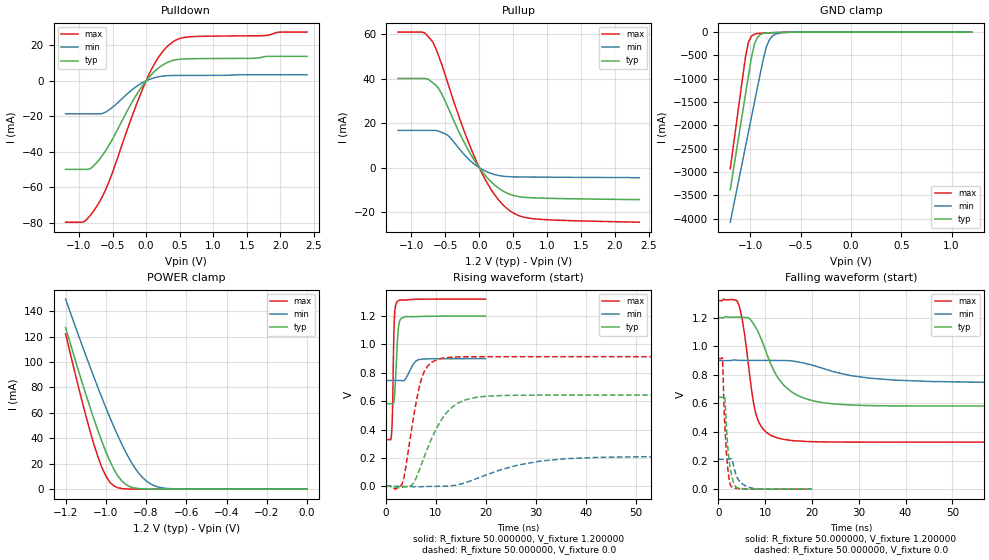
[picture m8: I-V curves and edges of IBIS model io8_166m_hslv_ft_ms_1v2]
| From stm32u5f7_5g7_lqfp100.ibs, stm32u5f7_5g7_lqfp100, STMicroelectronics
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|   Model io8_166m_hslv_ft_ms_1v2
[Model]  io8_166m_hslv_ft_ms_1v2
Model_type I/O
Polarity   Non-Inverting
Enable   Active-Low
Vinl =   0.360000V
Vinh =   0.840000V
Vmeas =  0.600000V
Cref =   50.000000pF
Rref =   100.000000M
Vref =   0.0V
C_comp   3.151700pF   3.087200pF   3.197900pF
[Temperature Range]   25.000000   0.140000k   -40.000000
[Pullup Reference]   1.200000V   0.900000V   1.320000V
[Pulldown Reference]   0.0V   0.0V   0.0V
[POWER Clamp Reference]   1.200000V   0.900000V   1.320000V
[GND Clamp Reference]   0.0V   0.0V   0.0V
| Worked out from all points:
|   slope of the pulldown table from 0 to 0.18 V, typ, clamps not added: 25.4 ohm
|   slope of the pullup table from 0 to 0.18 V, typ, clamps not added: 27.8 ohm
|   GND clamp passes 1 mA (typ) near -0.51 V on its own axis
|   POWER clamp passes 1 mA (typ) near -0.86 V on its own axis
|   rising waveform, R_fixture 50.000000, V_fixture 1.200000: 20-80 % time 554ps typ, 1.42ns min, 312ps max; typ from 0.582 V to 1.2 V
|   rising waveform, R_fixture 50.000000, V_fixture 0.0: 20-80 % time 5.22ns typ, 12.1ns min, 2.72ns max; typ from 0 V to 0.643 V
|   falling waveform, R_fixture 50.000000, V_fixture 1.200000: 20-80 % time 5.91ns typ, 12.5ns min, 2.6ns max; typ from 1.2 V to 0.582 V
|   falling waveform, R_fixture 50.000000, V_fixture 0.0: 20-80 % time 1.04ns typ, 1.73ns min, 827ps max; typ from 0.643 V to 0 V
[Pulldown]
|Voltage   I(typ)   I(min)   I(max)
-1.2V     -49.86mA   -18.57mA   -79.57mA
-920mV    -49.86mA   -18.57mA   -79.2mA
-840mV    -49.6mA    -18.57mA   -76.08mA
-720mV    -45.32mA   -18.57mA   -69.74mA
-560mV    -36.71mA   -16.58mA   -57.44mA
-200mV    -11.43mA   -4.74mA    -19.03mA
0V        10fA       -600fA     0A
160mV     6.477mA    2.075mA    11.78mA
360mV     10.99mA    2.99mA     20.81mA
480mV     12.07mA    3.054mA    23.53mA
640mV     12.43mA    3.074mA    24.76mA
2.4V      13.79mA    3.434mA    27.44mA
[Pullup]
|Voltage   I(typ)   I(min)   I(max)
-1.2V     40.08mA    16.78mA    60.92mA
-840mV    40.08mA    16.78mA    60.92mA
-680mV    38mA       16.78mA    56.18mA
-600mV    35.64mA    16.38mA    50.28mA
-480mV    28.32mA    14.86mA    39.46mA
-240mV    12.39mA    6.513mA    17.85mA
-40mV     1.772mA    818.2uA    2.67mA
200mV     -7.072mA   -2.851mA   -11mA
440mV     -11.84mA   -4.03mA    -19.1mA
600mV     -13.07mA   -4.154mA   -21.71mA
840mV     -13.59mA   -4.223mA   -23.04mA
2.36V     -14.3mA    -4.5mA     -24.47mA
[GND_clamp]
|Voltage   I(typ)   I(min)   I(max)
-1.2V     -3.379A    -4.076A    -2.932A
-1.05V    -1.35A     -2.47A     -550.7mA
-1.02V    -947.8mA   -2.149A    -221.5mA
-990mV    -552.4mA   -1.829A    -88.44mA
-960mV    -255.3mA   -1.51A     -44.87mA
-930mV    -111.8mA   -1.191A    -30.68mA
-870mV    -28.36mA   -564.6mA   -21.34mA
-840mV    -18.65mA   -309.5mA   -18.49mA
-810mV    -14.07mA   -161.6mA   -15.92mA
-780mV    -11.37mA   -83.33mA   -13.53mA
-600mV    -3.009mA   -4.322mA   -3.091mA
1.2V      0A         13.65nA    0A
[POWER_clamp]
|Voltage   I(typ)   I(min)   I(max)
-1.2V     127mA      149.4mA    122.2mA
-1.12V    84.97mA    114mA      70.27mA
-1.06V    55.51mA    88.42mA    35.67mA
-1.02V    37.63mA    72.04mA    17.17mA
-1V       29.51mA    64.13mA    10.3mA
-960mV    15.69mA    48.99mA    2.571mA
-900mV    3.624mA    28.77mA    182.8uA
-840mV    490.7uA    13.24mA    11.35uA
-800mV    116.8uA    6.532mA    1.77uA
-740mV    13.2uA     1.723mA    109.1nA
-620mV    167.4nA    79.36uA    0A
0V        0A         17.87nA    0A
[Ramp]
| variable   typ   min   max
dV/dt_r  0.38564/5.20998n   0.12553/12.05424n   0.54825/2.70923n
dV/dt_f  0.37086/5.90683n   92.48400m/12.46988n 0.59438/2.58443n
R_load = 50.000000
[Rising Waveform]
R_fixture= 50.000000
V_fixture= 1.200000
V_fixture_min= 0.900000
V_fixture_max= 1.320000
|time   V(typ)   V(min)   V(max)
0s        581.9mV    745.9mV    329.4mV
1.121ns   582.1mV    745.9mV    361.2mV
1.321ns   579.8mV    745.9mV    514.9mV
1.562ns   586.4mV    745.9mV    1.004V
1.682ns   618.9mV    745.9mV    1.163V
2.282ns   1.004V     746mV      1.302V
2.723ns   1.16V      746mV      1.312V
3.644ns   1.193V     746mV      1.313V
6.527ns   1.197V     892.2mV    1.319V
19.94ns   1.2V       900mV      1.32V
[Rising Waveform]
R_fixture= 50.000000
V_fixture= 0.0
V_fixture_min= 0.0
V_fixture_max= 0.0
|time   V(typ)   V(min)   V(max)
0s        1.999nV    239.2nV    1.184nV
3.203ns   -9.399mV   133.6uV    12.26mV
5.205ns   8.903mV    -3.023mV   414.4mV
7.207ns   162.4mV    -3.186mV   766mV
9.209ns   340.2mV    -711.5uV   874.7mV
12.01ns   511.7mV    591.5uV    906.2mV
18.82ns   630.1mV    62.96mV    913.5mV
30.83ns   642.3mV    176.8mV    913.7mV
42.84ns   642.6mV    204.1mV    913.7mV
199.4ns   642.7mV    209.3mV    913.8mV
[Falling Waveform]
R_fixture= 50.000000
V_fixture= 1.200000
V_fixture_min= 0.900000
V_fixture_max= 1.320000
|time   V(typ)   V(min)   V(max)
0s        1.2V       900mV      1.32V
4.004ns   1.204V     902.5mV    1.32V
5.205ns   1.203V     901.2mV    1.173V
7.207ns   1.173V     901mV      675mV
8.408ns   1.11V      901.1mV    490mV
12.01ns   820.6mV    900.9mV    366mV
14.41ns   715.6mV    900.2mV    346.1mV
22.82ns   603.6mV    840.6mV    330.6mV
45.65ns   582.2mV    753.4mV    329.3mV
199.4ns   581.9mV    745.9mV    329.4mV
[Falling Waveform]
R_fixture= 50.000000
V_fixture= 0.0
V_fixture_min= 0.0
V_fixture_max= 0.0
|time   V(typ)   V(min)   V(max)
0s        642.7mV    209.3mV    913.8mV
920.9ps   643mV      209.3mV    908.9mV
1.241ns   648.3mV    209.4mV    573.7mV
1.401ns   645mV      209.4mV    462.4mV
1.722ns   457.6mV    209.4mV    272.2mV
2.202ns   238.2mV    209.3mV    100.8mV
2.763ns   113mV      214.8mV    20.3mV
3.764ns   15.87mV    105.5mV    5.837mV
6.286ns   2.691mV    16.64mV    1.214mV
19.94ns   1.999nV    239.2nV    1.184nV
